VERSION 5.8 ;
BUSBITCHARS "[]" ;

UNITS
  DATABASE MICRONS 1000 ;
END UNITS

PROPERTYDEFINITIONS
  MACRO expanded_util REAL ;
END PROPERTYDEFINITIONS

LAYER OVERLAP
  TYPE OVERLAP ;
END OVERLAP

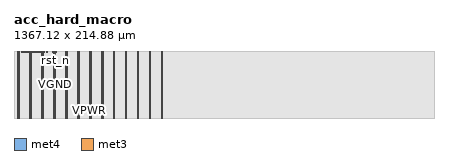
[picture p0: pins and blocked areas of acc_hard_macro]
MACRO acc_hard_macro
  CLASS BLOCK ;
  ORIGIN 0 0 ;
  SIZE 1367.12 BY 214.88 ;
  SYMMETRY X Y ;
  PIN uart_rx_i
    DIRECTION INPUT ;
    USE SIGNAL ;
    PORT
      LAYER met4 ;
        RECT 124.51 213.88 124.81 214.88 ;
    END
    ANTENNAPARTIALMETALAREA 0 ;
    ANTENNAPARTIALMETALSIDEAREA 0 ;
  END uart_rx_i
  PIN uo_out[7]
    DIRECTION OUTPUT ;
    USE SIGNAL ;
    PORT
      LAYER met4 ;
        RECT 69.31 213.88 69.61 214.88 ;
    END
    ANTENNAPARTIALMETALAREA 0 ;
    ANTENNAPARTIALMETALSIDEAREA 0 ;
  END uo_out[7]
  PIN uo_out[6]
    DIRECTION OUTPUT ;
    USE SIGNAL ;
    PORT
      LAYER met4 ;
        RECT 72.07 213.88 72.37 214.88 ;
    END
    ANTENNAPARTIALMETALAREA 0 ;
    ANTENNAPARTIALMETALSIDEAREA 0 ;
  END uo_out[6]
  PIN uo_out[5]
    DIRECTION OUTPUT ;
    USE SIGNAL ;
    PORT
      LAYER met4 ;
        RECT 74.83 213.88 75.13 214.88 ;
    END
    ANTENNAPARTIALMETALAREA 0 ;
    ANTENNAPARTIALMETALSIDEAREA 0 ;
  END uo_out[5]
  PIN uo_out[4]
    DIRECTION OUTPUT ;
    USE SIGNAL ;
    PORT
      LAYER met4 ;
        RECT 77.59 213.88 77.89 214.88 ;
    END
    ANTENNAPARTIALMETALAREA 0 ;
    ANTENNAPARTIALMETALSIDEAREA 0 ;
  END uo_out[4]
  PIN uo_out[3]
    DIRECTION OUTPUT ;
    USE SIGNAL ;
    PORT
      LAYER met4 ;
        RECT 80.35 213.88 80.65 214.88 ;
    END
    ANTENNAPARTIALMETALAREA 0 ;
    ANTENNAPARTIALMETALSIDEAREA 0 ;
  END uo_out[3]
  PIN uo_out[2]
    DIRECTION OUTPUT ;
    USE SIGNAL ;
    PORT
      LAYER met4 ;
        RECT 83.11 213.88 83.41 214.88 ;
    END
    ANTENNAPARTIALMETALAREA 0 ;
    ANTENNAPARTIALMETALSIDEAREA 0 ;
  END uo_out[2]
  PIN uo_out[1]
    DIRECTION OUTPUT ;
    USE SIGNAL ;
    PORT
      LAYER met4 ;
        RECT 85.87 213.88 86.17 214.88 ;
    END
    ANTENNAPARTIALMETALAREA 0 ;
    ANTENNAPARTIALMETALSIDEAREA 0 ;
  END uo_out[1]
  PIN uo_out[0]
    DIRECTION OUTPUT ;
    USE SIGNAL ;
    PORT
      LAYER met4 ;
        RECT 88.63 213.88 88.93 214.88 ;
    END
    ANTENNAPARTIALMETALAREA 0 ;
    ANTENNAPARTIALMETALSIDEAREA 0 ;
  END uo_out[0]
  PIN qspi_dq_i[3]
    DIRECTION INPUT ;
    USE SIGNAL ;
    PORT
      LAYER met4 ;
        RECT 96.91 213.88 97.21 214.88 ;
    END
    ANTENNAPARTIALMETALAREA 0 ;
    ANTENNAPARTIALMETALSIDEAREA 0 ;
  END qspi_dq_i[3]
  PIN qspi_dq_i[2]
    DIRECTION INPUT ;
    USE SIGNAL ;
    PORT
      LAYER met4 ;
        RECT 99.67 213.88 99.97 214.88 ;
    END
    ANTENNAPARTIALMETALAREA 0 ;
    ANTENNAPARTIALMETALSIDEAREA 0 ;
  END qspi_dq_i[2]
  PIN qspi_dq_i[1]
    DIRECTION INPUT ;
    USE SIGNAL ;
    PORT
      LAYER met4 ;
        RECT 105.19 213.88 105.49 214.88 ;
    END
    ANTENNAPARTIALMETALAREA 0 ;
    ANTENNAPARTIALMETALSIDEAREA 0 ;
  END qspi_dq_i[1]
  PIN qspi_dq_i[0]
    DIRECTION INPUT ;
    USE SIGNAL ;
    PORT
      LAYER met4 ;
        RECT 107.95 213.88 108.25 214.88 ;
    END
    ANTENNAPARTIALMETALAREA 0 ;
    ANTENNAPARTIALMETALSIDEAREA 0 ;
  END qspi_dq_i[0]
  PIN uio_out[7]
    DIRECTION OUTPUT ;
    USE SIGNAL ;
    PORT
      LAYER met4 ;
        RECT 47.23 213.88 47.53 214.88 ;
    END
    ANTENNAPARTIALMETALAREA 0 ;
    ANTENNAPARTIALMETALSIDEAREA 0 ;
  END uio_out[7]
  PIN uio_out[6]
    DIRECTION OUTPUT ;
    USE SIGNAL ;
    PORT
      LAYER met4 ;
        RECT 49.99 213.88 50.29 214.88 ;
    END
    ANTENNAPARTIALMETALAREA 0 ;
    ANTENNAPARTIALMETALSIDEAREA 0 ;
  END uio_out[6]
  PIN uio_out[5]
    DIRECTION OUTPUT ;
    USE SIGNAL ;
    PORT
      LAYER met3 ;
        RECT 52.75 213.88 53.05 214.88 ;
    END
    ANTENNAPARTIALMETALAREA 0 ;
    ANTENNAPARTIALMETALSIDEAREA 0 ;
  END uio_out[5]
  PIN uio_out[4]
    DIRECTION OUTPUT ;
    USE SIGNAL ;
    PORT
      LAYER met3 ;
        RECT 55.51 213.88 55.81 214.88 ;
    END
    ANTENNAPARTIALMETALAREA 0 ;
    ANTENNAPARTIALMETALSIDEAREA 0 ;
  END uio_out[4]
  PIN uio_out[3]
    DIRECTION OUTPUT ;
    USE SIGNAL ;
    PORT
      LAYER met4 ;
        RECT 58.27 213.88 58.57 214.88 ;
    END
    ANTENNAPARTIALMETALAREA 0 ;
    ANTENNAPARTIALMETALSIDEAREA 0 ;
  END uio_out[3]
  PIN uio_out[2]
    DIRECTION OUTPUT ;
    USE SIGNAL ;
    PORT
      LAYER met4 ;
        RECT 61.03 213.88 61.33 214.88 ;
    END
    ANTENNAPARTIALMETALAREA 0 ;
    ANTENNAPARTIALMETALSIDEAREA 0 ;
  END uio_out[2]
  PIN uio_out[1]
    DIRECTION OUTPUT ;
    USE SIGNAL ;
    PORT
      LAYER met4 ;
        RECT 63.79 213.88 64.09 214.88 ;
    END
    ANTENNAPARTIALMETALAREA 0 ;
    ANTENNAPARTIALMETALSIDEAREA 0 ;
  END uio_out[1]
  PIN uio_out[0]
    DIRECTION OUTPUT ;
    USE SIGNAL ;
    PORT
      LAYER met4 ;
        RECT 66.55 213.88 66.85 214.88 ;
    END
    ANTENNAPARTIALMETALAREA 0 ;
    ANTENNAPARTIALMETALSIDEAREA 0 ;
  END uio_out[0]
  PIN uio_oe[7]
    DIRECTION OUTPUT ;
    USE SIGNAL ;
    PORT
      LAYER met4 ;
        RECT 25.15 213.88 25.45 214.88 ;
    END
    ANTENNAPARTIALMETALAREA 0 ;
    ANTENNAPARTIALMETALSIDEAREA 0 ;
  END uio_oe[7]
  PIN uio_oe[6]
    DIRECTION OUTPUT ;
    USE SIGNAL ;
    PORT
      LAYER met4 ;
        RECT 27.91 213.88 28.21 214.88 ;
    END
    ANTENNAPARTIALMETALAREA 0 ;
    ANTENNAPARTIALMETALSIDEAREA 0 ;
  END uio_oe[6]
  PIN uio_oe[5]
    DIRECTION OUTPUT ;
    USE SIGNAL ;
    PORT
      LAYER met4 ;
        RECT 30.67 213.88 30.97 214.88 ;
    END
    ANTENNAPARTIALMETALAREA 0 ;
    ANTENNAPARTIALMETALSIDEAREA 0 ;
  END uio_oe[5]
  PIN uio_oe[4]
    DIRECTION OUTPUT ;
    USE SIGNAL ;
    PORT
      LAYER met4 ;
        RECT 33.43 213.88 33.73 214.88 ;
    END
    ANTENNAPARTIALMETALAREA 0 ;
    ANTENNAPARTIALMETALSIDEAREA 0 ;
  END uio_oe[4]
  PIN uio_oe[3]
    DIRECTION OUTPUT ;
    USE SIGNAL ;
    PORT
      LAYER met4 ;
        RECT 36.19 213.88 36.49 214.88 ;
    END
    ANTENNAPARTIALMETALAREA 0 ;
    ANTENNAPARTIALMETALSIDEAREA 0 ;
  END uio_oe[3]
  PIN uio_oe[2]
    DIRECTION OUTPUT ;
    USE SIGNAL ;
    PORT
      LAYER met4 ;
        RECT 38.95 213.88 39.25 214.88 ;
    END
    ANTENNAPARTIALMETALAREA 0 ;
    ANTENNAPARTIALMETALSIDEAREA 0 ;
  END uio_oe[2]
  PIN uio_oe[1]
    DIRECTION OUTPUT ;
    USE SIGNAL ;
    PORT
      LAYER met4 ;
        RECT 41.71 213.88 42.01 214.88 ;
    END
    ANTENNAPARTIALMETALAREA 0 ;
    ANTENNAPARTIALMETALSIDEAREA 0 ;
  END uio_oe[1]
  PIN uio_oe[0]
    DIRECTION OUTPUT ;
    USE SIGNAL ;
    PORT
      LAYER met4 ;
        RECT 44.47 213.88 44.77 214.88 ;
    END
    ANTENNAPARTIALMETALAREA 0 ;
    ANTENNAPARTIALMETALSIDEAREA 0 ;
  END uio_oe[0]
  PIN clk
    DIRECTION INPUT ;
    USE CLOCK ;
    PORT
      LAYER met4 ;
        RECT 138.31 213.88 138.61 214.88 ;
    END
    ANTENNAPARTIALMETALAREA 0 ;
    ANTENNAPARTIALMETALSIDEAREA 0 ;
  END clk
  PIN rst_n
    DIRECTION INPUT ;
    USE SIGNAL ;
    PORT
      LAYER met4 ;
        RECT 135.55 213.88 135.85 214.88 ;
    END
    ANTENNAPARTIALMETALAREA 0 ;
    ANTENNAPARTIALMETALSIDEAREA 0 ;
  END rst_n
  PIN VPWR
    DIRECTION INPUT ;
    USE POWER ;
    PORT
      LAYER met4 ;
        RECT 12.76 0 14.36 214.88 ;
        RECT 51.63 0 53.23 214.88 ;
        RECT 90.5 0 92.1 214.88 ;
        RECT 129.37 0 130.97 214.88 ;
        RECT 168.24 0 169.84 214.88 ;
        RECT 207.11 0 208.71 214.88 ;
        RECT 245.98 0 247.58 214.88 ;
        RECT 284.85 0 286.45 214.88 ;
        RECT 323.72 0 325.32 214.88 ;
        RECT 362.59 0 364.19 214.88 ;
        RECT 401.46 0 403.06 214.88 ;
        RECT 440.33 0 441.93 214.88 ;
        RECT 479.2 0 480.8 214.88 ;
    END
    ANTENNAPARTIALMETALAREA 0 ;
    ANTENNAPARTIALMETALSIDEAREA 0 ;
  END VPWR
  PIN VGND
    DIRECTION INPUT ;
    USE GROUND ;
    PORT
      LAYER met4 ;
        RECT 16.06 0 17.66 214.88 ;
        RECT 54.93 0 56.53 214.88 ;
        RECT 93.8 0 95.4 214.88 ;
        RECT 132.67 0 134.27 214.88 ;
        RECT 171.54 0 173.14 214.88 ;
        RECT 210.41 0 212.01 214.88 ;
        RECT 249.28 0 250.88 214.88 ;
        RECT 288.15 0 289.75 214.88 ;
        RECT 327.02 0 328.62 214.88 ;
        RECT 365.89 0 367.49 214.88 ;
        RECT 404.76 0 406.36 214.88 ;
        RECT 443.63 0 445.23 214.88 ;
        RECT 482.5 0 484.1 214.88 ;
    END
    ANTENNAPARTIALMETALAREA 0 ;
    ANTENNAPARTIALMETALSIDEAREA 0 ;
  END VGND
  OBS
    LAYER li1 ;
      RECT 504.785 0.155 1367.12 214.73 ;
    LAYER li1 SPACING 0 ;
      RECT 0 0 1367.12 214.88 ;
    LAYER met1 SPACING 0 ;
      RECT 0 0.59 1367.12 211.99 ;
    LAYER met2 SPACING 0 ;
      RECT 0 0 1367.12 214.88 ;
    LAYER met3 SPACING 0 ;
      POLYGON 1367.12 214.88 1367.12 0 0 0 0 214.88 52.75 214.88 52.75 213.88 53.05 213.88 53.05 214.88 55.51 214.88 55.51 213.88 55.81 213.88 55.81 214.88 ;
    LAYER met4 SPACING 0 ;
      POLYGON
        51.63 0 51.63 214.88 50.29 214.88 50.29 213.88
        49.99 213.88 49.99 214.88 47.53 214.88 47.53 213.88
        47.23 213.88 47.23 214.88 44.77 214.88 44.77 213.88
        44.47 213.88 44.47 214.88 42.01 214.88 42.01 213.88
        41.71 213.88 41.71 214.88 39.25 214.88 39.25 213.88
        38.95 213.88 38.95 214.88 36.49 214.88 36.49 213.88
        36.19 213.88 36.19 214.88 33.73 214.88 33.73 213.88
        33.43 213.88 33.43 214.88 30.97 214.88 30.97 213.88
        30.67 213.88 30.67 214.88 28.21 214.88 28.21 213.88
        27.91 213.88 27.91 214.88 25.45 214.88 25.45 213.88
        25.15 213.88 25.15 214.88 17.66 214.88 17.66 0 ;
      POLYGON
        1367.12 0 1367.12 214.88 484.1 214.88 484.1 0 ;
      POLYGON
        482.5 0 482.5 214.88 480.8 214.88 480.8 0 ;
      POLYGON
        16.06 0 16.06 214.88 14.36 214.88 14.36 0 ;
      POLYGON
        12.76 214.88 0 214.88 0 0 12.76 0 ;
      POLYGON
        210.41 0 210.41 214.88 208.71 214.88 208.71 0 ;
      POLYGON
        93.8 0 93.8 214.88 92.1 214.88 92.1 0 ;
      POLYGON
        129.37 0 129.37 214.88 124.81 214.88 124.81 213.88
        124.51 213.88 124.51 214.88 108.25 214.88 108.25 213.88
        107.95 213.88 107.95 214.88 105.49 214.88 105.49 213.88
        105.19 213.88 105.19 214.88 99.97 214.88 99.97 213.88
        99.67 213.88 99.67 214.88 97.21 214.88 97.21 213.88
        96.91 213.88 96.91 214.88 95.4 214.88 95.4 0 ;
      POLYGON
        132.67 0 132.67 214.88 130.97 214.88 130.97 0 ;
      POLYGON
        168.24 0 168.24 214.88 138.61 214.88 138.61 213.88
        138.31 213.88 138.31 214.88 135.85 214.88 135.85 213.88
        135.55 213.88 135.55 214.88 134.27 214.88 134.27 0 ;
      POLYGON
        171.54 0 171.54 214.88 169.84 214.88 169.84 0 ;
      POLYGON
        207.11 0 207.11 214.88 173.14 214.88 173.14 0 ;
      POLYGON
        90.5 0 90.5 214.88 88.93 214.88 88.93 213.88
        88.63 213.88 88.63 214.88 86.17 214.88 86.17 213.88
        85.87 213.88 85.87 214.88 83.41 214.88 83.41 213.88
        83.11 213.88 83.11 214.88 80.65 214.88 80.65 213.88
        80.35 213.88 80.35 214.88 77.89 214.88 77.89 213.88
        77.59 213.88 77.59 214.88 75.13 214.88 75.13 213.88
        74.83 213.88 74.83 214.88 72.37 214.88 72.37 213.88
        72.07 213.88 72.07 214.88 69.61 214.88 69.61 213.88
        69.31 213.88 69.31 214.88 66.85 214.88 66.85 213.88
        66.55 213.88 66.55 214.88 64.09 214.88 64.09 213.88
        63.79 213.88 63.79 214.88 61.33 214.88 61.33 213.88
        61.03 213.88 61.03 214.88 58.57 214.88 58.57 213.88
        58.27 213.88 58.27 214.88 56.53 214.88 56.53 0 ;
      POLYGON
        245.98 0 245.98 214.88 212.01 214.88 212.01 0 ;
      POLYGON
        249.28 0 249.28 214.88 247.58 214.88 247.58 0 ;
      POLYGON
        284.85 0 284.85 214.88 250.88 214.88 250.88 0 ;
      POLYGON
        288.15 0 288.15 214.88 286.45 214.88 286.45 0 ;
      POLYGON
        323.72 0 323.72 214.88 289.75 214.88 289.75 0 ;
      POLYGON
        327.02 0 327.02 214.88 325.32 214.88 325.32 0 ;
      POLYGON
        362.59 0 362.59 214.88 328.62 214.88 328.62 0 ;
      POLYGON
        365.89 0 365.89 214.88 364.19 214.88 364.19 0 ;
      POLYGON
        401.46 0 401.46 214.88 367.49 214.88 367.49 0 ;
      POLYGON
        404.76 0 404.76 214.88 403.06 214.88 403.06 0 ;
      POLYGON
        440.33 0 440.33 214.88 406.36 214.88 406.36 0 ;
      POLYGON
        443.63 0 443.63 214.88 441.93 214.88 441.93 0 ;
      POLYGON
        479.2 0 479.2 214.88 445.23 214.88 445.23 0 ;
      POLYGON
        54.93 0 54.93 214.88 53.23 214.88 53.23 0 ;
    LAYER via3 SPACING 0 ;
      RECT 1356.63 214.13 1357.23 214.73 ;
      RECT 1355.95 214.13 1356.55 214.73 ;
      RECT 1355.27 214.13 1355.87 214.73 ;
      RECT 516.035 214.13 516.635 214.73 ;
      RECT 515.355 214.13 515.955 214.73 ;
      RECT 514.675 214.13 515.275 214.73 ;
      RECT 1356.63 0.155 1357.23 0.755 ;
      RECT 1355.95 0.155 1356.55 0.755 ;
      RECT 1355.27 0.155 1355.87 0.755 ;
      RECT 516.035 0.155 516.635 0.755 ;
      RECT 515.355 0.155 515.955 0.755 ;
      RECT 514.675 0.155 515.275 0.755 ;
    LAYER nwell SPACING 0 ;
      RECT 0 0 1367.12 214.88 ;
    LAYER pwell SPACING 0 ;
      RECT 0 0 1367.12 214.88 ;
    LAYER met4 ;
      POLYGON
        516.525 0.4 1355.38 0.4 1355.38 0.265 1357.12 0.265
        1357.12 0.4 1366.72 0.4 1366.72 214.48 1357.12 214.48
        1357.12 214.62 1355.38 214.62 1355.38 214.48 516.525 214.48
        516.525 214.62 514.785 214.62 514.785 214.48 484.5 214.48
        484.5 213.48 484.1 213.48 484.1 1.4 484.5 1.4
        484.5 0.4 514.785 0.4 514.785 0.265 516.525 0.265 ;
      POLYGON
        478.8 1.4 479.2 1.4 479.2 213.48 478.8 213.48
        478.8 214.48 445.63 214.48 445.63 213.48 445.23 213.48
        445.23 1.4 445.63 1.4 445.63 0.4 478.8 0.4 ;
      POLYGON
        12.36 1.4 12.76 1.4 12.76 213.48 12.36 213.48
        12.36 214.48 0.4 214.48 0.4 0.4 12.36 0.4 ;
      POLYGON
        15.66 1.4 16.06 1.4 16.06 213.48 15.66 213.48
        15.66 214.48 14.76 214.48 14.76 213.48 14.36 213.48
        14.36 1.4 14.76 1.4 14.76 0.4 15.66 0.4 ;
      POLYGON
        51.23 1.4 51.63 1.4 51.63 213.48 51.23 213.48
        51.23 214.48 50.69 214.48 50.69 213.48 49.59 213.48
        49.59 214.48 47.93 214.48 47.93 213.48 46.83 213.48
        46.83 214.48 45.17 214.48 45.17 213.48 44.07 213.48
        44.07 214.48 42.41 214.48 42.41 213.48 41.31 213.48
        41.31 214.48 39.65 214.48 39.65 213.48 38.55 213.48
        38.55 214.48 36.89 214.48 36.89 213.48 35.79 213.48
        35.79 214.48 34.13 214.48 34.13 213.48 33.03 213.48
        33.03 214.48 31.37 214.48 31.37 213.48 30.27 213.48
        30.27 214.48 28.61 214.48 28.61 213.48 27.51 213.48
        27.51 214.48 25.85 214.48 25.85 213.48 24.75 213.48
        24.75 214.48 18.06 214.48 18.06 213.48 17.66 213.48
        17.66 1.4 18.06 1.4 18.06 0.4 51.23 0.4 ;
      POLYGON
        206.71 1.4 207.11 1.4 207.11 213.48 206.71 213.48
        206.71 214.48 173.54 214.48 173.54 213.48 173.14 213.48
        173.14 1.4 173.54 1.4 173.54 0.4 206.71 0.4 ;
      POLYGON
        90.1 1.4 90.5 1.4 90.5 213.48 90.1 213.48
        90.1 214.48 89.33 214.48 89.33 213.48 88.23 213.48
        88.23 214.48 86.57 214.48 86.57 213.48 85.47 213.48
        85.47 214.48 83.81 214.48 83.81 213.48 82.71 213.48
        82.71 214.48 81.05 214.48 81.05 213.48 79.95 213.48
        79.95 214.48 78.29 214.48 78.29 213.48 77.19 213.48
        77.19 214.48 75.53 214.48 75.53 213.48 74.43 213.48
        74.43 214.48 72.77 214.48 72.77 213.48 71.67 213.48
        71.67 214.48 70.01 214.48 70.01 213.48 68.91 213.48
        68.91 214.48 67.25 214.48 67.25 213.48 66.15 213.48
        66.15 214.48 64.49 214.48 64.49 213.48 63.39 213.48
        63.39 214.48 61.73 214.48 61.73 213.48 60.63 213.48
        60.63 214.48 58.97 214.48 58.97 213.48 57.87 213.48
        57.87 214.48 56.93 214.48 56.93 213.48 56.53 213.48
        56.53 1.4 56.93 1.4 56.93 0.4 90.1 0.4 ;
      POLYGON
        93.4 1.4 93.8 1.4 93.8 213.48 93.4 213.48
        93.4 214.48 92.5 214.48 92.5 213.48 92.1 213.48
        92.1 1.4 92.5 1.4 92.5 0.4 93.4 0.4 ;
      POLYGON
        128.97 1.4 129.37 1.4 129.37 213.48 128.97 213.48
        128.97 214.48 125.21 214.48 125.21 213.48 124.11 213.48
        124.11 214.48 108.65 214.48 108.65 213.48 107.55 213.48
        107.55 214.48 105.89 214.48 105.89 213.48 104.79 213.48
        104.79 214.48 100.37 214.48 100.37 213.48 99.27 213.48
        99.27 214.48 97.61 214.48 97.61 213.48 96.51 213.48
        96.51 214.48 95.8 214.48 95.8 213.48 95.4 213.48
        95.4 1.4 95.8 1.4 95.8 0.4 128.97 0.4 ;
      POLYGON
        132.27 1.4 132.67 1.4 132.67 213.48 132.27 213.48
        132.27 214.48 131.37 214.48 131.37 213.48 130.97 213.48
        130.97 1.4 131.37 1.4 131.37 0.4 132.27 0.4 ;
      POLYGON
        167.84 1.4 168.24 1.4 168.24 213.48 167.84 213.48
        167.84 214.48 139.01 214.48 139.01 213.48 137.91 213.48
        137.91 214.48 136.25 214.48 136.25 213.48 135.15 213.48
        135.15 214.48 134.67 214.48 134.67 213.48 134.27 213.48
        134.27 1.4 134.67 1.4 134.67 0.4 167.84 0.4 ;
      POLYGON
        171.14 1.4 171.54 1.4 171.54 213.48 171.14 213.48
        171.14 214.48 170.24 214.48 170.24 213.48 169.84 213.48
        169.84 1.4 170.24 1.4 170.24 0.4 171.14 0.4 ;
      POLYGON
        54.53 1.4 54.93 1.4 54.93 213.48 54.53 213.48
        54.53 214.48 53.63 214.48 53.63 213.48 53.23 213.48
        53.23 1.4 53.63 1.4 53.63 0.4 54.53 0.4 ;
      POLYGON
        210.01 1.4 210.41 1.4 210.41 213.48 210.01 213.48
        210.01 214.48 209.11 214.48 209.11 213.48 208.71 213.48
        208.71 1.4 209.11 1.4 209.11 0.4 210.01 0.4 ;
      POLYGON
        245.58 1.4 245.98 1.4 245.98 213.48 245.58 213.48
        245.58 214.48 212.41 214.48 212.41 213.48 212.01 213.48
        212.01 1.4 212.41 1.4 212.41 0.4 245.58 0.4 ;
      POLYGON
        248.88 1.4 249.28 1.4 249.28 213.48 248.88 213.48
        248.88 214.48 247.98 214.48 247.98 213.48 247.58 213.48
        247.58 1.4 247.98 1.4 247.98 0.4 248.88 0.4 ;
      POLYGON
        284.45 1.4 284.85 1.4 284.85 213.48 284.45 213.48
        284.45 214.48 251.28 214.48 251.28 213.48 250.88 213.48
        250.88 1.4 251.28 1.4 251.28 0.4 284.45 0.4 ;
      POLYGON
        287.75 1.4 288.15 1.4 288.15 213.48 287.75 213.48
        287.75 214.48 286.85 214.48 286.85 213.48 286.45 213.48
        286.45 1.4 286.85 1.4 286.85 0.4 287.75 0.4 ;
      POLYGON
        323.32 1.4 323.72 1.4 323.72 213.48 323.32 213.48
        323.32 214.48 290.15 214.48 290.15 213.48 289.75 213.48
        289.75 1.4 290.15 1.4 290.15 0.4 323.32 0.4 ;
      POLYGON
        326.62 1.4 327.02 1.4 327.02 213.48 326.62 213.48
        326.62 214.48 325.72 214.48 325.72 213.48 325.32 213.48
        325.32 1.4 325.72 1.4 325.72 0.4 326.62 0.4 ;
      POLYGON
        362.19 1.4 362.59 1.4 362.59 213.48 362.19 213.48
        362.19 214.48 329.02 214.48 329.02 213.48 328.62 213.48
        328.62 1.4 329.02 1.4 329.02 0.4 362.19 0.4 ;
      POLYGON
        365.49 1.4 365.89 1.4 365.89 213.48 365.49 213.48
        365.49 214.48 364.59 214.48 364.59 213.48 364.19 213.48
        364.19 1.4 364.59 1.4 364.59 0.4 365.49 0.4 ;
      POLYGON
        401.06 1.4 401.46 1.4 401.46 213.48 401.06 213.48
        401.06 214.48 367.89 214.48 367.89 213.48 367.49 213.48
        367.49 1.4 367.89 1.4 367.89 0.4 401.06 0.4 ;
      POLYGON
        404.36 1.4 404.76 1.4 404.76 213.48 404.36 213.48
        404.36 214.48 403.46 214.48 403.46 213.48 403.06 213.48
        403.06 1.4 403.46 1.4 403.46 0.4 404.36 0.4 ;
      POLYGON
        439.93 1.4 440.33 1.4 440.33 213.48 439.93 213.48
        439.93 214.48 406.76 214.48 406.76 213.48 406.36 213.48
        406.36 1.4 406.76 1.4 406.76 0.4 439.93 0.4 ;
      POLYGON
        443.23 1.4 443.63 1.4 443.63 213.48 443.23 213.48
        443.23 214.48 442.33 214.48 442.33 213.48 441.93 213.48
        441.93 1.4 442.33 1.4 442.33 0.4 443.23 0.4 ;
      POLYGON
        482.1 1.4 482.5 1.4 482.5 213.48 482.1 213.48
        482.1 214.48 481.2 214.48 481.2 213.48 480.8 213.48
        480.8 1.4 481.2 1.4 481.2 0.4 482.1 0.4 ;
    LAYER met3 ;
      RECT 479.2 212.88 1357.12 214.62 ;
      RECT 479.2 0.265 1357.12 2.005 ;
      POLYGON 1366.72 214.48 1366.72 0.4 0.4 0.4 0.4 214.48 52.35 214.48 52.35 213.48 53.45 213.48 53.45 214.48 55.11 214.48 55.11 213.48 56.21 213.48 56.21 214.48 ;
    LAYER li1 ;
      RECT 0.34 0.34 1366.78 214.54 ;
    LAYER met1 ;
      RECT 0.28 0.59 1366.84 211.99 ;
    LAYER met2 ;
      RECT 0.28 0.28 1366.84 214.6 ;
    LAYER via3 ;
      RECT 480.5 214.25 480.7 214.45 ;
      RECT 480.1 214.25 480.3 214.45 ;
      RECT 479.7 214.25 479.9 214.45 ;
      RECT 479.3 214.25 479.5 214.45 ;
      RECT 42.18 214.14 42.38 214.34 ;
      RECT 39.42 214.14 39.62 214.34 ;
      RECT 33.9 214.14 34.1 214.34 ;
      RECT 480.5 213.85 480.7 214.05 ;
      RECT 480.1 213.85 480.3 214.05 ;
      RECT 479.7 213.85 479.9 214.05 ;
      RECT 479.3 213.85 479.5 214.05 ;
      RECT 124.06 213.46 124.26 213.66 ;
      RECT 480.5 213.45 480.7 213.65 ;
      RECT 480.1 213.45 480.3 213.65 ;
      RECT 479.7 213.45 479.9 213.65 ;
      RECT 479.3 213.45 479.5 213.65 ;
      RECT 480.5 1.235 480.7 1.435 ;
      RECT 480.1 1.235 480.3 1.435 ;
      RECT 479.7 1.235 479.9 1.435 ;
      RECT 479.3 1.235 479.5 1.435 ;
      RECT 480.5 0.835 480.7 1.035 ;
      RECT 480.1 0.835 480.3 1.035 ;
      RECT 479.7 0.835 479.9 1.035 ;
      RECT 479.3 0.835 479.5 1.035 ;
      RECT 480.5 0.435 480.7 0.635 ;
      RECT 480.1 0.435 480.3 0.635 ;
      RECT 479.7 0.435 479.9 0.635 ;
      RECT 479.3 0.435 479.5 0.635 ;
    LAYER nwell ;
      RECT 0 0 1367.12 214.88 ;
    LAYER pwell ;
      RECT 0 0 1367.12 214.88 ;
    LAYER OVERLAP ;
      POLYGON 0 0 0 214.88 1367.12 214.88 1367.12 0 ;
  END
  PROPERTY expanded_util 0.62 ;
END acc_hard_macro

END LIBRARY
